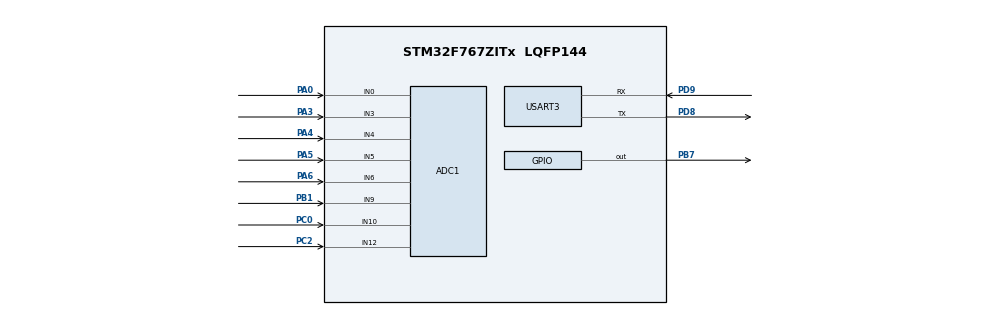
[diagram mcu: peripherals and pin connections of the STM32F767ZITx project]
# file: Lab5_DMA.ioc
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ADC1.Channel-0\#ChannelRegularConversion=ADC_CHANNEL_0
ADC1.Channel-1\#ChannelRegularConversion=ADC_CHANNEL_3
ADC1.Channel-2\#ChannelRegularConversion=ADC_CHANNEL_4
ADC1.Channel-3\#ChannelRegularConversion=ADC_CHANNEL_5
ADC1.Channel-4\#ChannelRegularConversion=ADC_CHANNEL_6
ADC1.Channel-5\#ChannelRegularConversion=ADC_CHANNEL_9
ADC1.Channel-6\#ChannelRegularConversion=ADC_CHANNEL_10
ADC1.Channel-7\#ChannelRegularConversion=ADC_CHANNEL_12
ADC1.ContinuousConvMode=ENABLE
ADC1.DMAContinuousRequests=ENABLE
ADC1.NbrOfConversion=8
ADC1.NbrOfConversionFlag=1
ADC1.Rank-0\#ChannelRegularConversion=1
ADC1.Rank-1\#ChannelRegularConversion=2
ADC1.Rank-2\#ChannelRegularConversion=3
ADC1.Rank-3\#ChannelRegularConversion=4
ADC1.Rank-4\#ChannelRegularConversion=5
ADC1.Rank-5\#ChannelRegularConversion=6
ADC1.Rank-6\#ChannelRegularConversion=7
ADC1.Rank-7\#ChannelRegularConversion=8
ADC1.SamplingTime-0\#ChannelRegularConversion=ADC_SAMPLETIME_3CYCLES
ADC1.SamplingTime-1\#ChannelRegularConversion=ADC_SAMPLETIME_3CYCLES
ADC1.SamplingTime-2\#ChannelRegularConversion=ADC_SAMPLETIME_3CYCLES
ADC1.SamplingTime-3\#ChannelRegularConversion=ADC_SAMPLETIME_3CYCLES
ADC1.SamplingTime-4\#ChannelRegularConversion=ADC_SAMPLETIME_3CYCLES
ADC1.SamplingTime-5\#ChannelRegularConversion=ADC_SAMPLETIME_3CYCLES
ADC1.SamplingTime-6\#ChannelRegularConversion=ADC_SAMPLETIME_3CYCLES
ADC1.SamplingTime-7\#ChannelRegularConversion=ADC_SAMPLETIME_3CYCLES
ADC1.ScanConvMode=ADC_SCAN_ENABLE
ADC1.master=1
CORTEX_M7.default_mode_Activation=1
Dma.ADC1.0.Direction=DMA_PERIPH_TO_MEMORY
Dma.ADC1.0.FIFOMode=DMA_FIFOMODE_DISABLE
Dma.ADC1.0.Instance=DMA2_Stream0
Dma.ADC1.0.MemDataAlignment=DMA_MDATAALIGN_WORD
Dma.ADC1.0.MemInc=DMA_MINC_ENABLE
Dma.ADC1.0.Mode=DMA_CIRCULAR
Dma.ADC1.0.PeriphDataAlignment=DMA_PDATAALIGN_WORD
Dma.ADC1.0.PeriphInc=DMA_PINC_DISABLE
Dma.ADC1.0.Priority=DMA_PRIORITY_LOW
Dma.Request0=ADC1
Mcu.Family=STM32F7
Mcu.Name=STM32F767ZITx
Mcu.Package=LQFP144
NVIC.DMA2_Stream0_IRQn=true\:2\:0\:true\:false\:true\:false\:true\:true
NVIC.PriorityGroup=NVIC_PRIORITYGROUP_4
PA0/WKUP.Signal=ADCx_IN0
PA3.Signal=ADCx_IN3
PA4.Signal=ADCx_IN4
PA5.Signal=ADCx_IN5
PA6.Signal=ADCx_IN6
PB1.Signal=ADCx_IN9
PB7.Signal=GPIO_Output
PC0.Signal=ADCx_IN10
PC2.Signal=ADCx_IN12
PD8.Mode=Asynchronous
PD8.Signal=USART3_TX
PD9.Mode=Asynchronous
PD9.Signal=USART3_RX
ProjectManager.HeapSize=0x200
ProjectManager.StackSize=0x400
ProjectManager.TargetToolchain=Makefile
RCC.HSE_VALUE=25000000
RCC.HSI_VALUE=16000000
RCC.LSE_VALUE=32768
RCC.USBFreq_Value=96000000
RCC.VCOOutputFreq_Value=192000000
SH.ADCx_IN0.0=ADC1_IN0,IN0
SH.ADCx_IN10.0=ADC1_IN10,IN10
SH.ADCx_IN12.0=ADC1_IN12,IN12
SH.ADCx_IN3.0=ADC1_IN3,IN3
SH.ADCx_IN4.0=ADC1_IN4,IN4
SH.ADCx_IN5.0=ADC1_IN5,IN5
SH.ADCx_IN6.0=ADC1_IN6,IN6
SH.ADCx_IN9.0=ADC1_IN9,IN9
USART3.VirtualMode-Asynchronous=VM_ASYNC
board=custom

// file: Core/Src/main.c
/* USER CODE BEGIN Header */
/**
  ******************************************************************************
  * @file           : main.c
  * @brief          : Main program body
  ******************************************************************************
  * @attention
  *
  * Copyright (c) 2025 STMicroelectronics.
  * All rights reserved.
  *
  * This software is licensed under terms that can be found in the LICENSE file
  * in the root directory of this software component.
  * If no LICENSE file comes with this software, it is provided AS-IS.
  *
  ******************************************************************************
  */
/* USER CODE END Header */
#include "main.h"
#include "adc.h"
#include "dma.h"
#include "usart.h"
#include "gpio.h"

/* USER CODE BEGIN Includes */
#include <stdio.h>
#include <string.h>
/* USER CODE END Includes */

void SystemClock_Config(void);
/* USER CODE BEGIN PFP */
void transmitUARTStr(char* str);
void transmitUARTChar(char c);
void displayHEX(uint32_t dec);
/* USER CODE END PFP */

int main(void)
{

  /* MCU Configuration--------------------------------------------------------*/

  /* Reset of all peripherals, Initializes the Flash interface and the Systick. */
  HAL_Init();

  /* Configure the system clock */
  SystemClock_Config();

  /* Initialize all configured peripherals */
  MX_GPIO_Init();
  MX_DMA_Init();
  MX_ADC1_Init();
  MX_USART3_UART_Init();

  /* Infinite loop */
  /* USER CODE BEGIN WHILE */
  uint32_t adc_val = 0;
  HAL_ADC_Start_DMA(&hadc1, &adc_val, 1);
  while (1)
  {
    /* USER CODE END WHILE */

    /* USER CODE BEGIN 3 */
    // while (HAL_ADC_PollForConversion(&hadc1, 100) != HAL_OK) {}
    transmitUARTStr("ADC1_CH10 ");

    displayHEX(adc_val);

    char buf[20];
    float v_in = adc_val/4095.0 * 3.3;
    int int_part = (int)v_in;
    int dec_part = (int)((v_in - int_part) * 100);
    sprintf(buf, "%d.%02d", int_part, dec_part);
    transmitUARTStr(" Vin = ");
    transmitUARTStr(buf);
    transmitUARTStr("\r\n");
    HAL_Delay(400);
  }
  /* USER CODE END 3 */
}

void SystemClock_Config(void)
{
  RCC_OscInitTypeDef RCC_OscInitStruct = {0};
  RCC_ClkInitTypeDef RCC_ClkInitStruct = {0};

  /** Configure the main internal regulator output voltage
  */
  __HAL_RCC_PWR_CLK_ENABLE();
  __HAL_PWR_VOLTAGESCALING_CONFIG(PWR_REGULATOR_VOLTAGE_SCALE3);

  /** Initializes the RCC Oscillators according to the specified parameters
  * in the RCC_OscInitTypeDef structure.
  */
  RCC_OscInitStruct.OscillatorType = RCC_OSCILLATORTYPE_HSI;
  RCC_OscInitStruct.HSIState = RCC_HSI_ON;
  RCC_OscInitStruct.HSICalibrationValue = RCC_HSICALIBRATION_DEFAULT;
  RCC_OscInitStruct.PLL.PLLState = RCC_PLL_ON;
  RCC_OscInitStruct.PLL.PLLSource = RCC_PLLSOURCE_HSI;
  RCC_OscInitStruct.PLL.PLLM = 8;
  RCC_OscInitStruct.PLL.PLLN = 96;
  RCC_OscInitStruct.PLL.PLLP = RCC_PLLP_DIV2;
  RCC_OscInitStruct.PLL.PLLQ = 4;
  RCC_OscInitStruct.PLL.PLLR = 2;
  if (HAL_RCC_OscConfig(&RCC_OscInitStruct) != HAL_OK)
  {
    Error_Handler();
  }

  /** Activate the Over-Drive mode
  */
  if (HAL_PWREx_EnableOverDrive() != HAL_OK)
  {
    Error_Handler();
  }

  /** Initializes the CPU, AHB and APB buses clocks
  */
  RCC_ClkInitStruct.ClockType = RCC_CLOCKTYPE_HCLK|RCC_CLOCKTYPE_SYSCLK
                              |RCC_CLOCKTYPE_PCLK1|RCC_CLOCKTYPE_PCLK2;
  RCC_ClkInitStruct.SYSCLKSource = RCC_SYSCLKSOURCE_PLLCLK;
  RCC_ClkInitStruct.AHBCLKDivider = RCC_SYSCLK_DIV1;
  RCC_ClkInitStruct.APB1CLKDivider = RCC_HCLK_DIV2;
  RCC_ClkInitStruct.APB2CLKDivider = RCC_HCLK_DIV1;

  if (HAL_RCC_ClockConfig(&RCC_ClkInitStruct, FLASH_LATENCY_3) != HAL_OK)
  {
    Error_Handler();
  }
}

/* USER CODE BEGIN 4 */
void transmitUARTStr(char* str){
  while (__HAL_UART_GET_FLAG(&huart3, UART_FLAG_TC)==RESET){}
  HAL_UART_Transmit(&huart3, (uint8_t*)str, strlen(str), 1000);
}

void transmitUARTChar(char c){
  while (__HAL_UART_GET_FLAG(&huart3, UART_FLAG_TC)==RESET){}
  HAL_UART_Transmit(&huart3, (uint8_t*)&c, 1, 1000);
}

void displayHEX(uint32_t dec){
  char buf[13];
  sprintf(buf, "0x%08x", (unsigned int)dec);
  transmitUARTStr(buf);
}
/* USER CODE END 4 */

void Error_Handler(void)
{
  __disable_irq();
  while (1)
  {
  }
}
